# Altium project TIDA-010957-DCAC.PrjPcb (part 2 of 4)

## Sheet TIDA-010957-DCAC-Switching-Stage-GaN-TOLT.SchDoc
size 558 x 431 mm; Date: Not shown in title block; ApprovedBy: Not shown in title block; CheckedBy: Not shown in title block; Author: Not shown in title block; CompanyName: Not shown in title block; Engineer: Not shown in title block; Organization: Not shown in title block; Address1: Not shown in title block; Address2: Not shown in title block; Address3: Not shown in title block; Address4: Not shown in title block; DocumentNumber: 1; Revision: Use project parameter SCH_Rev; SheetNumber: 12; SheetTotal: 12; PageSetup: Record=PageOptions¦CenterHorizontal=True¦CenterVertical=True¦PrintScale=1.00¦XCorrection=1.00¦YCorrection=1.00¦PrintKind=0¦BorderSize=5000000¦LeftOffset=0¦BottomOffset=0¦Orientation=2¦PaperLength=1000¦PaperWidth=1000¦Scale=100¦PaperSource=15¦PrintQuality=600¦MediaType=1¦DitherType=10¦PaperKind=Letter¦PrintScaleMode=1
Used 4 times, as channels N, L1, L2, L3. Parts and nets are listed once, with the designators drawn on the sheet.

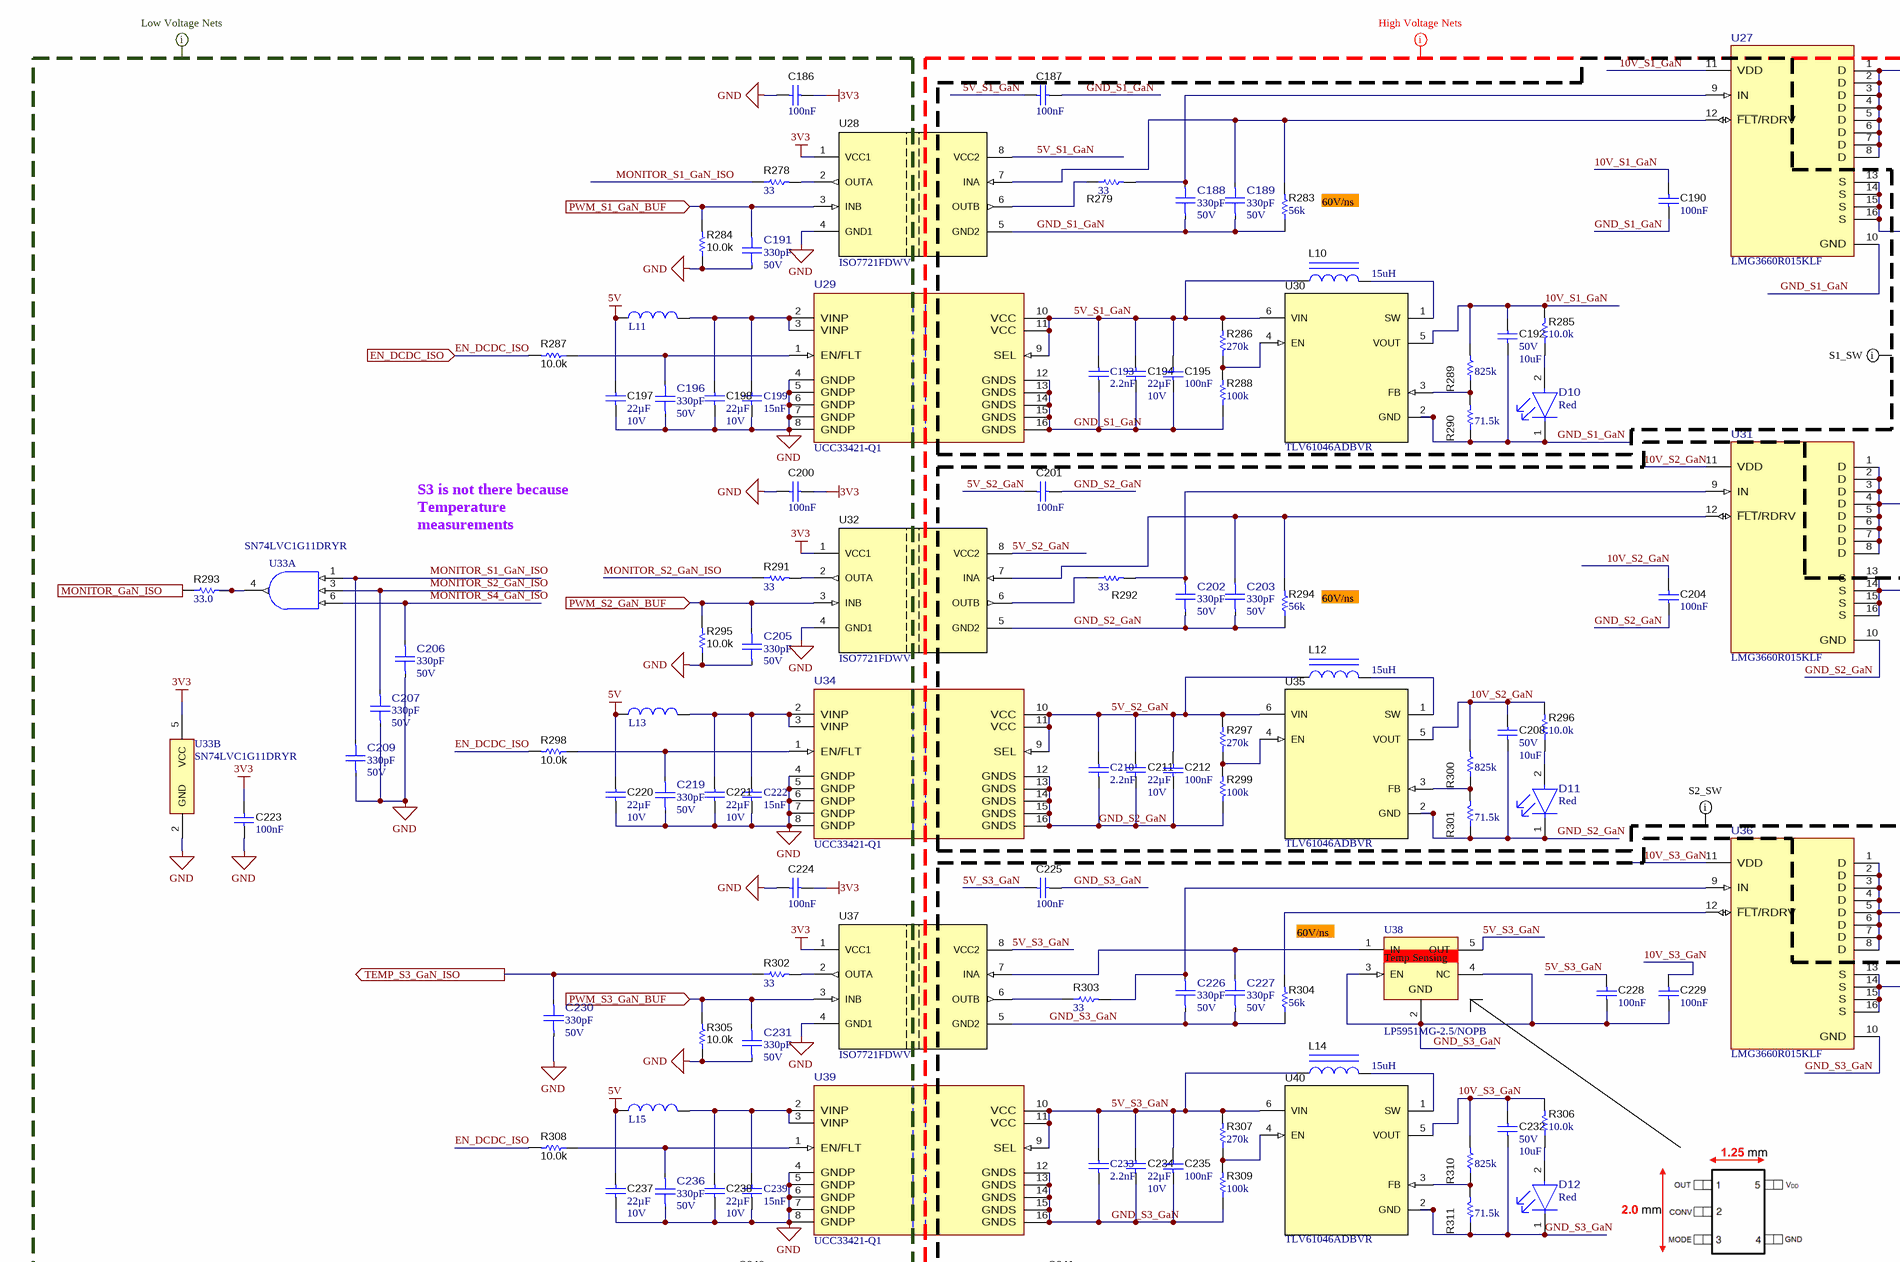
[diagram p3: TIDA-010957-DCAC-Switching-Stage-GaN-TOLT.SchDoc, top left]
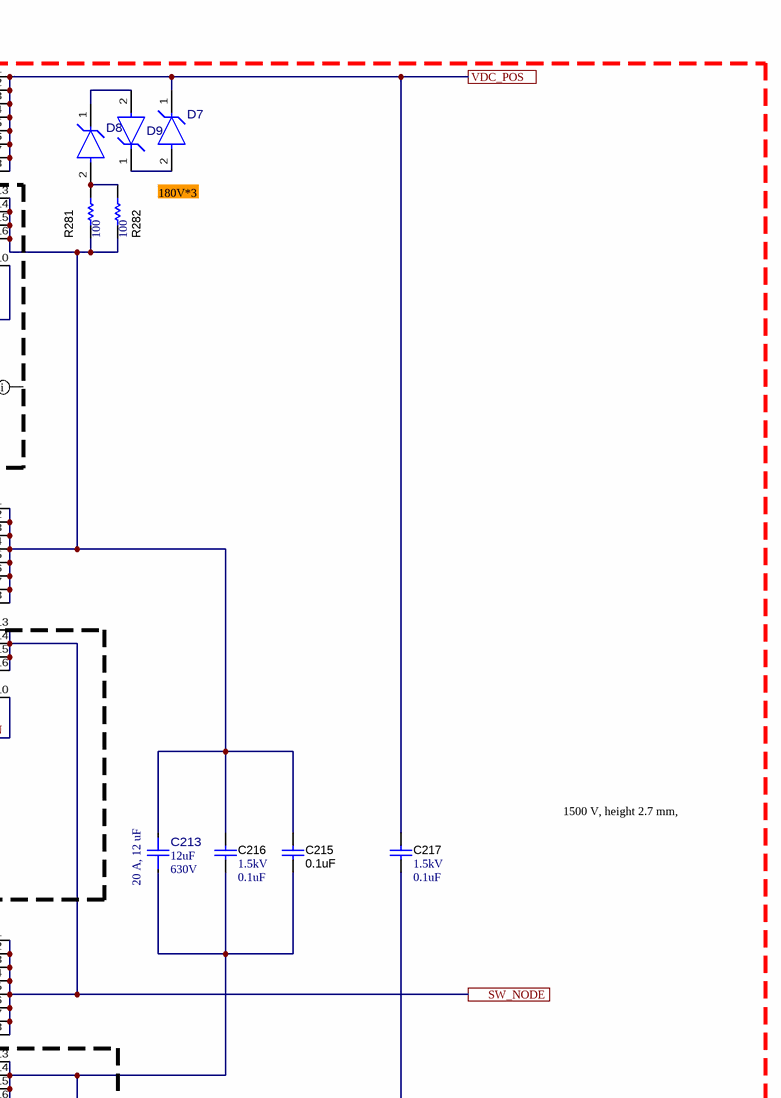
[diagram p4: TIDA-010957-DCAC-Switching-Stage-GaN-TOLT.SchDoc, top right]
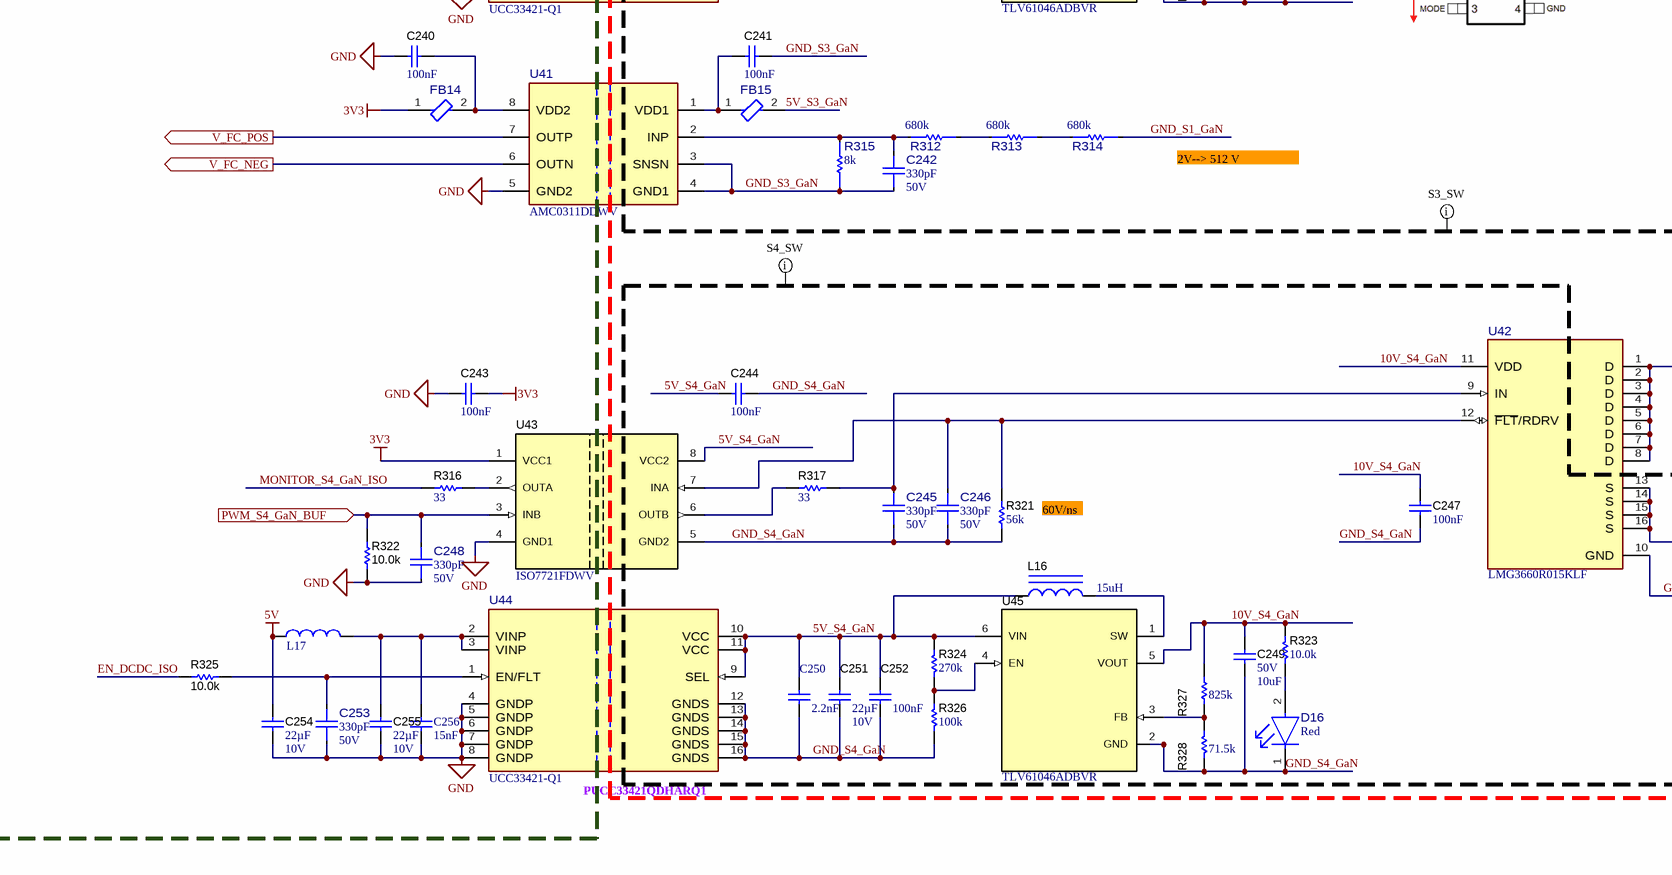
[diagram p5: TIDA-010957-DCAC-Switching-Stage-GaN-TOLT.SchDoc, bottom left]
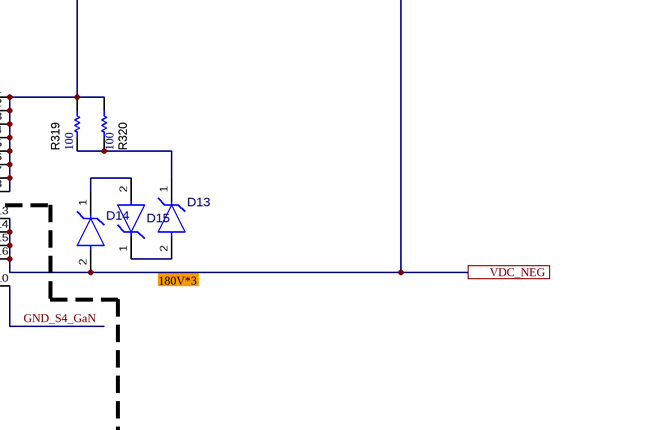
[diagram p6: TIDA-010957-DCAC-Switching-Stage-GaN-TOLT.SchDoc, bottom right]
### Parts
C186  Cap_F: 100nF  [0603]  (hidden comment: 06033C104JAT2A)
C187  Cap_F: 100nF  [0603]  (hidden comment: 06033C104JAT2A)
C188  ValueDisplayed: 330pF  VDC_V: 50V  [FP-CGA3E2C0G1H331J080AA_0603-MFG]  (hidden comment: CGA3E2C0G1H331J080AA)
C189  ValueDisplayed: 330pF  VDC_V: 50V  [FP-CGA3E2C0G1H331J080AA_0603-MFG]  (hidden comment: CGA3E2C0G1H331J080AA)
C190  Cap_F: 100nF  [0603]  (hidden comment: 06033C104JAT2A)
C191  ValueDisplayed: 330pF  VDC_V: 50V  [FP-CGA3E2C0G1H331J080AA_0603-MFG]  (hidden comment: CGA3E2C0G1H331J080AA)
C192  VDC_V: 50V  ValueDisplayed: 10uF  [1206_180]  (hidden comment: GRT31CR61H106KE01L)
C193  Cap_F: 2.2nF  [WCAP-CSGP_0402_L1W0.5H0.5]  (hidden comment: 885012205063)
C194  Cap_F: 22µF  VDC_V: 10V  [0805_HV]  (hidden comment: GRM21BZ71A226ME15L)
C195  Cap_F: 100nF  [0603]  (hidden comment: 06033C104JAT2A)
C196  ValueDisplayed: 330pF  VDC_V: 50V  [FP-CGA3E2C0G1H331J080AA_0603-MFG]  (hidden comment: CGA3E2C0G1H331J080AA)
C197  Cap_F: 22µF  VDC_V: 10V  [0805_HV]  (hidden comment: GRM21BZ71A226ME15L)
C198  Cap_F: 22µF  VDC_V: 10V  [0805_HV]  (hidden comment: GRM21BZ71A226ME15L)
C199  Cap_F: 15nF  [WCAP-CSGP_0402_L1W0.5H0.5]  (hidden comment: 885012205051)
C200  Cap_F: 100nF  [0603]  (hidden comment: 06033C104JAT2A)
C201  Cap_F: 100nF  [0603]  (hidden comment: 06033C104JAT2A)
C202  ValueDisplayed: 330pF  VDC_V: 50V  [FP-CGA3E2C0G1H331J080AA_0603-MFG]  (hidden comment: CGA3E2C0G1H331J080AA)
C203  ValueDisplayed: 330pF  VDC_V: 50V  [FP-CGA3E2C0G1H331J080AA_0603-MFG]  (hidden comment: CGA3E2C0G1H331J080AA)
C204  Cap_F: 100nF  [0603]  (hidden comment: 06033C104JAT2A)
C205  ValueDisplayed: 330pF  VDC_V: 50V  [FP-CGA3E2C0G1H331J080AA_0603-MFG]  (hidden comment: CGA3E2C0G1H331J080AA)
C206  ValueDisplayed: 330pF  VDC_V: 50V  [FP-CGA3E2C0G1H331J080AA_0603-MFG]  (hidden comment: CGA3E2C0G1H331J080AA)
C207  ValueDisplayed: 330pF  VDC_V: 50V  [FP-CGA3E2C0G1H331J080AA_0603-MFG]  (hidden comment: CGA3E2C0G1H331J080AA)
C208  VDC_V: 50V  ValueDisplayed: 10uF  [1206_180]  (hidden comment: GRT31CR61H106KE01L)
C209  ValueDisplayed: 330pF  VDC_V: 50V  [FP-CGA3E2C0G1H331J080AA_0603-MFG]  (hidden comment: CGA3E2C0G1H331J080AA)
C210  Cap_F: 2.2nF  [WCAP-CSGP_0402_L1W0.5H0.5]  (hidden comment: 885012205063)
C211  Cap_F: 22µF  VDC_V: 10V  [0805_HV]  (hidden comment: GRM21BZ71A226ME15L)
C212  Cap_F: 100nF  [0603]  (hidden comment: 06033C104JAT2A)
C213  ValueDisplayed: 12uF  VDC_V: 630V  [FP-B32676G6126K000_RADIAL-MFG]  (hidden comment: B32676G6126K000)
C215  ValueDisplayed: 0.1uF  [1812_254]  (hidden comment: C1812W104KDRACTU)
C216  VDC_V: 1.5kV  ValueDisplayed: 0.1uF  [2225]  (hidden comment: C2225C104KFRACTU)
C217  VDC_V: 1.5kV  ValueDisplayed: 0.1uF  [2225]  (hidden comment: C2225C104KFRACTU)
C219  ValueDisplayed: 330pF  VDC_V: 50V  [FP-CGA3E2C0G1H331J080AA_0603-MFG]  (hidden comment: CGA3E2C0G1H331J080AA)
C220  Cap_F: 22µF  VDC_V: 10V  [0805_HV]  (hidden comment: GRM21BZ71A226ME15L)
C221  Cap_F: 22µF  VDC_V: 10V  [0805_HV]  (hidden comment: GRM21BZ71A226ME15L)
C222  Cap_F: 15nF  [WCAP-CSGP_0402_L1W0.5H0.5]  (hidden comment: 885012205051)
C223  Cap_F: 100nF  [0603]  (hidden comment: 06033C104JAT2A)
C224  Cap_F: 100nF  [0603]  (hidden comment: 06033C104JAT2A)
C225  Cap_F: 100nF  [0603]  (hidden comment: 06033C104JAT2A)
C226  ValueDisplayed: 330pF  VDC_V: 50V  [FP-CGA3E2C0G1H331J080AA_0603-MFG]  (hidden comment: CGA3E2C0G1H331J080AA)
C227  ValueDisplayed: 330pF  VDC_V: 50V  [FP-CGA3E2C0G1H331J080AA_0603-MFG]  (hidden comment: CGA3E2C0G1H331J080AA)
C228  Cap_F: 100nF  [0603]  (hidden comment: 06033C104JAT2A)
C229  Cap_F: 100nF  [0603]  (hidden comment: 06033C104JAT2A)
C230  ValueDisplayed: 330pF  VDC_V: 50V  [FP-CGA3E2C0G1H331J080AA_0603-MFG]  (hidden comment: CGA3E2C0G1H331J080AA)
C231  ValueDisplayed: 330pF  VDC_V: 50V  [FP-CGA3E2C0G1H331J080AA_0603-MFG]  (hidden comment: CGA3E2C0G1H331J080AA)
C232  VDC_V: 50V  ValueDisplayed: 10uF  [1206_180]  (hidden comment: GRT31CR61H106KE01L)
C233  Cap_F: 2.2nF  [WCAP-CSGP_0402_L1W0.5H0.5]  (hidden comment: 885012205063)
C234  Cap_F: 22µF  VDC_V: 10V  [0805_HV]  (hidden comment: GRM21BZ71A226ME15L)
C235  Cap_F: 100nF  [0603]  (hidden comment: 06033C104JAT2A)
C236  ValueDisplayed: 330pF  VDC_V: 50V  [FP-CGA3E2C0G1H331J080AA_0603-MFG]  (hidden comment: CGA3E2C0G1H331J080AA)
C237  Cap_F: 22µF  VDC_V: 10V  [0805_HV]  (hidden comment: GRM21BZ71A226ME15L)
C238  Cap_F: 22µF  VDC_V: 10V  [0805_HV]  (hidden comment: GRM21BZ71A226ME15L)
C239  Cap_F: 15nF  [WCAP-CSGP_0402_L1W0.5H0.5]  (hidden comment: 885012205051)
C240  Cap_F: 100nF  [0603]  (hidden comment: 06033C104JAT2A)
C241  Cap_F: 100nF  [0603]  (hidden comment: 06033C104JAT2A)
C242  ValueDisplayed: 330pF  VDC_V: 50V  [FP-CGA3E2C0G1H331J080AA_0603-MFG]  (hidden comment: CGA3E2C0G1H331J080AA)
C243  Cap_F: 100nF  [0603]  (hidden comment: 06033C104JAT2A)
C244  Cap_F: 100nF  [0603]  (hidden comment: 06033C104JAT2A)
C245  ValueDisplayed: 330pF  VDC_V: 50V  [FP-CGA3E2C0G1H331J080AA_0603-MFG]  (hidden comment: CGA3E2C0G1H331J080AA)
C246  ValueDisplayed: 330pF  VDC_V: 50V  [FP-CGA3E2C0G1H331J080AA_0603-MFG]  (hidden comment: CGA3E2C0G1H331J080AA)
C247  Cap_F: 100nF  [0603]  (hidden comment: 06033C104JAT2A)
C248  ValueDisplayed: 330pF  VDC_V: 50V  [FP-CGA3E2C0G1H331J080AA_0603-MFG]  (hidden comment: CGA3E2C0G1H331J080AA)
C249  VDC_V: 50V  ValueDisplayed: 10uF  [1206_180]  (hidden comment: GRT31CR61H106KE01L)
C250  Cap_F: 2.2nF  [WCAP-CSGP_0402_L1W0.5H0.5]  (hidden comment: 885012205063)
C251  Cap_F: 22µF  VDC_V: 10V  [0805_HV]  (hidden comment: GRM21BZ71A226ME15L)
C252  Cap_F: 100nF  [0603]  (hidden comment: 06033C104JAT2A)
C253  ValueDisplayed: 330pF  VDC_V: 50V  [FP-CGA3E2C0G1H331J080AA_0603-MFG]  (hidden comment: CGA3E2C0G1H331J080AA)
C254  Cap_F: 22µF  VDC_V: 10V  [0805_HV]  (hidden comment: GRM21BZ71A226ME15L)
C255  Cap_F: 22µF  VDC_V: 10V  [0805_HV]  (hidden comment: GRM21BZ71A226ME15L)
C256  Cap_F: 15nF  [WCAP-CSGP_0402_L1W0.5H0.5]  (hidden comment: 885012205051)
D7  ZGL41-180A-E3/96  [FP-ZGL41-180A-E3/96_GL41-MFG]  (value not drawn)
D8  ZGL41-180A-E3/96  [FP-ZGL41-180A-E3/96_GL41-MFG]  (value not drawn)
D9  ZGL41-180A-E3/96  [FP-ZGL41-180A-E3/96_GL41-MFG]  (value not drawn)
D10  Color: Red  [FP-APG1608SURKC_T_0603-MFG]  (hidden comment: APG1608SURKC/T)
D11  Color: Red  [FP-APG1608SURKC_T_0603-MFG]  (hidden comment: APG1608SURKC/T)
D12  Color: Red  [FP-APG1608SURKC_T_0603-MFG]  (hidden comment: APG1608SURKC/T)
D13  ZGL41-180A-E3/96  [FP-ZGL41-180A-E3/96_GL41-MFG]  (value not drawn)
D14  ZGL41-180A-E3/96  [FP-ZGL41-180A-E3/96_GL41-MFG]  (value not drawn)
D15  ZGL41-180A-E3/96  [FP-ZGL41-180A-E3/96_GL41-MFG]  (value not drawn)
D16  Color: Red  [FP-APG1608SURKC_T_0603-MFG]  (hidden comment: APG1608SURKC/T)
FB14  MH1608-601Y  [FP-MH1608-601Y_0603-MFG]  (value not drawn)
FB15  MH1608-601Y  [FP-MH1608-601Y_0603-MFG]  (value not drawn)
L10  ValueDisplayed: 15uH  [SDR0302]  (hidden comment: SDR0302-150ML)
L11  74479763222  [WE-PMI_0603_L1.6W0.8H0.8]  (value not drawn)
L12  ValueDisplayed: 15uH  [SDR0302]  (hidden comment: SDR0302-150ML)
L13  74479763222  [WE-PMI_0603_L1.6W0.8H0.8]  (value not drawn)
L14  ValueDisplayed: 15uH  [SDR0302]  (hidden comment: SDR0302-150ML)
L15  74479763222  [WE-PMI_0603_L1.6W0.8H0.8]  (value not drawn)
L16  ValueDisplayed: 15uH  [SDR0302]  (hidden comment: SDR0302-150ML)
L17  74479763222  [WE-PMI_0603_L1.6W0.8H0.8]  (value not drawn)
R278  ValueDisplayed: 33  [0603]  (hidden comment: CRCW060333R0JNEA)
R279  ValueDisplayed: 33  [0603]  (hidden comment: CRCW060333R0JNEA)
R281  ValueDisplayed: 100  [1206]  (hidden comment: CRCW1206100RFKEAHP)
R282  ValueDisplayed: 100  [1206]  (hidden comment: CRCW1206100RFKEAHP)
R283  ValueDisplayed: 56k  [0603]  (hidden comment: CRCW060356K0JNEA)
R284  ValueDisplayed: 10.0k  [0603]  (hidden comment: CRCW060310K0FKEA)
R285  ValueDisplayed: 10.0k  [0603]  (hidden comment: RC0603FR-0710KL)
R286  ValueDisplayed: 270k  [0603]  (hidden comment: RC0603FR-07270KL)
R287  ValueDisplayed: 10.0k  [0603]  (hidden comment: CRCW060310K0FKEA)
R288  ValueDisplayed: 100k  [0603]  (hidden comment: RC0603FR-07100KL)
R289  ValueDisplayed: 825k  [0603]  (hidden comment: RC0603FR-07825KL)
R290  ValueDisplayed: 71.5k  [0603]  (hidden comment: RC0603FR-0771K5L)
R291  ValueDisplayed: 33  [0603]  (hidden comment: CRCW060333R0JNEA)
R292  ValueDisplayed: 33  [0603]  (hidden comment: CRCW060333R0JNEA)
R293  ValueDisplayed: 33.0  [0402L]  (hidden comment: ERJ-2RKF33R0X)
R294  ValueDisplayed: 56k  [0603]  (hidden comment: CRCW060356K0JNEA)
R295  ValueDisplayed: 10.0k  [0603]  (hidden comment: CRCW060310K0FKEA)
R296  ValueDisplayed: 10.0k  [0603]  (hidden comment: RC0603FR-0710KL)
R297  ValueDisplayed: 270k  [0603]  (hidden comment: RC0603FR-07270KL)
R298  ValueDisplayed: 10.0k  [0603]  (hidden comment: CRCW060310K0FKEA)
R299  ValueDisplayed: 100k  [0603]  (hidden comment: RC0603FR-07100KL)
R300  ValueDisplayed: 825k  [0603]  (hidden comment: RC0603FR-07825KL)
R301  ValueDisplayed: 71.5k  [0603]  (hidden comment: RC0603FR-0771K5L)
R302  ValueDisplayed: 33  [0603]  (hidden comment: CRCW060333R0JNEA)
R303  ValueDisplayed: 33  [0603]  (hidden comment: CRCW060333R0JNEA)
R304  ValueDisplayed: 56k  [0603]  (hidden comment: CRCW060356K0JNEA)
R305  ValueDisplayed: 10.0k  [0603]  (hidden comment: CRCW060310K0FKEA)
R306  ValueDisplayed: 10.0k  [0603]  (hidden comment: RC0603FR-0710KL)
R307  ValueDisplayed: 270k  [0603]  (hidden comment: RC0603FR-07270KL)
R308  ValueDisplayed: 10.0k  [0603]  (hidden comment: CRCW060310K0FKEA)
R309  ValueDisplayed: 100k  [0603]  (hidden comment: RC0603FR-07100KL)
R310  ValueDisplayed: 825k  [0603]  (hidden comment: RC0603FR-07825KL)
R311  ValueDisplayed: 71.5k  [0603]  (hidden comment: RC0603FR-0771K5L)
R312  value 680k  [FP-TNPV0805680KBEEA_0805-MFG]  (hidden comment: TNPV0805680KBEEA)
R313  value 680k  [FP-TNPV0805680KBEEA_0805-MFG]  (hidden comment: TNPV0805680KBEEA)
R314  value 680k  [FP-TNPV0805680KBEEA_0805-MFG]  (hidden comment: TNPV0805680KBEEA)
R315  value 8k  [FP-RT0603BRE078KL_0603-MFG]  (hidden comment: RT0603BRE078KL)
R316  ValueDisplayed: 33  [0603]  (hidden comment: CRCW060333R0JNEA)
R317  ValueDisplayed: 33  [0603]  (hidden comment: CRCW060333R0JNEA)
R319  ValueDisplayed: 100  [1206]  (hidden comment: CRCW1206100RFKEAHP)
R320  ValueDisplayed: 100  [1206]  (hidden comment: CRCW1206100RFKEAHP)
R321  ValueDisplayed: 56k  [0603]  (hidden comment: CRCW060356K0JNEA)
R322  ValueDisplayed: 10.0k  [0603]  (hidden comment: CRCW060310K0FKEA)
R323  ValueDisplayed: 10.0k  [0603]  (hidden comment: RC0603FR-0710KL)
R324  ValueDisplayed: 270k  [0603]  (hidden comment: RC0603FR-07270KL)
R325  ValueDisplayed: 10.0k  [0603]  (hidden comment: CRCW060310K0FKEA)
R326  ValueDisplayed: 100k  [0603]  (hidden comment: RC0603FR-07100KL)
R327  ValueDisplayed: 825k  [0603]  (hidden comment: RC0603FR-07825KL)
R328  ValueDisplayed: 71.5k  [0603]  (hidden comment: RC0603FR-0771K5L)
U27  LMG3660R015KLF  [KLF0016A-MFG]
U28  ISO7721FDWV  [DWV0008A]
U29  UCC33421-Q1  [DWX0016A-MFG]
U30  TLV61046ADBVR  [DBV0006A_N]
U31  LMG3660R015KLF  [KLF0016A-MFG]
U32  ISO7721FDWV  [DWV0008A]
U33  SN74LVC1G11DRYR  [DRY0006A]  (parts A,B of 2)
U34  UCC33421-Q1  [DWX0016A-MFG]
U35  TLV61046ADBVR  [DBV0006A_N]
U36  LMG3660R015KLF  [KLF0016A-MFG]
U37  ISO7721FDWV  [DWV0008A]
U38  LP5951MG-2.5/NOPB  [DCK0005A_N]
U39  UCC33421-Q1  [DWX0016A-MFG]
U40  TLV61046ADBVR  [DBV0006A_N]
U41  AMC0311DDWV  [DWV0008A-MFG]
U42  LMG3660R015KLF  [KLF0016A-MFG]
U43  ISO7721FDWV  [DWV0008A]
U44  UCC33421-Q1  [DWX0016A-MFG]
U45  TLV61046ADBVR  [DBV0006A_N]

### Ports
EN_DCDC_ISO (in), MONITOR_GaN_ISO (out), PWM_S1_GaN_BUF (in), PWM_S2_GaN_BUF (in), PWM_S3_GaN_BUF (in), PWM_S4_GaN_BUF (in), SW_NODE, TEMP_S3_GaN_ISO (out), V_FC_NEG (out), V_FC_POS (out), VDC_NEG, VDC_POS

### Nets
3V3: C186.1 C200.1 C223.1 C224.1 C243.1 FB14.1 U28.1(VCC1) U32.1(VCC1) U33.5(VCC) U37.1(VCC1) U43.1(VCC1)
5V: C197.1 C220.1 C237.1 C254.1 L11.2 L13.2 L15.2 L17.2
GND: C186.2 C191.1 C196.1 C197.2 C198.2 C199.1 C200.2 C205.1 C206.1 C207.1 C209.1 C219.1 C220.2 C221.2 C222.1 C223.2 C224.2 C230.1 C231.1 C236.1 C237.2 C238.2 C239.1 C240.2 C243.2 C248.1 C253.1 C254.2 C255.2 C256.1 R284.1 R295.1 R305.1 R322.1 U28.4(GND1) U29.4(GNDP) U29.5(GNDP) U29.6(GNDP) U29.7(GNDP) U29.8(GNDP) U32.4(GND1) U33.2(GND) U34.4(GNDP) U34.5(GNDP) U34.6(GNDP) U34.7(GNDP) U34.8(GNDP) U37.4(GND1) U39.4(GNDP) U39.5(GNDP) U39.6(GNDP) U39.7(GNDP) U39.8(GNDP) U41.5(GND2) U43.4(GND1) U44.4(GNDP) U44.5(GNDP) U44.6(GNDP) U44.7(GNDP) U44.8(GNDP)
5V_S1_GaN: C187.1 C193.2 C194.1 C195.1 L10.2 R286.2 U28.8(VCC2) U29.9(SEL) U29.10(VCC) U29.11(VCC) U30.6(VIN)
5V_S2_GaN: C201.1 C210.2 C211.1 C212.1 L12.2 R297.2 U32.8(VCC2) U34.9(SEL) U34.10(VCC) U34.11(VCC) U35.6(VIN)
5V_S3_GaN: C225.1 C228.1 C233.2 C234.1 C235.1 FB15.2 L14.2 R307.2 U37.8(VCC2) U38.5(OUT) U39.9(SEL) U39.10(VCC) U39.11(VCC) U40.6(VIN)
5V_S4_GaN: C244.1 C250.2 C251.1 C252.1 L16.2 R324.2 U43.8(VCC2) U44.9(SEL) U44.10(VCC) U44.11(VCC) U45.6(VIN)
10V_S1_GaN: C190.1 C192.1 R285.2 R289.2 U27.11(VDD) U30.5(VOUT)
10V_S2_GaN: C204.1 C208.1 R296.2 R300.2 U31.11(VDD) U35.5(VOUT)
10V_S3_GaN: C229.1 C232.1 R306.2 R310.2 U36.11(VDD) U40.5(VOUT)
10V_S4_GaN: C247.1 C249.1 R323.2 R327.2 U42.11(VDD) U45.5(VOUT)
EN_DCDC_ISO: R287.2 R298.2 R308.2 R325.2 ; port EN_DCDC_ISO
GND_S1_GaN: C187.2 C188.1 C189.1 C190.2 C192.2 C193.1 C194.2 C195.2 D10.1(CATHODE) R283.1 R288.1 R290.1 R314.2 U27.10(GND) U28.5(GND2) U29.12(GNDS) U29.13(GNDS) U29.14(GNDS) U29.15(GNDS) U29.16(GNDS) U30.2(GND)
GND_S2_GaN: C201.2 C202.1 C203.1 C204.2 C208.2 C210.1 C211.2 C212.2 D11.1(CATHODE) R294.1 R299.1 R301.1 U31.10(GND) U32.5(GND2) U34.12(GNDS) U34.13(GNDS) U34.14(GNDS) U34.15(GNDS) U34.16(GNDS) U35.2(GND)
GND_S3_GaN: C225.2 C226.1 C227.1 C228.2 C229.2 C232.2 C233.1 C234.2 C235.2 C241.2 C242.1 D12.1(CATHODE) R304.1 R309.1 R311.1 R315.1 U36.10(GND) U37.5(GND2) U38.2(GND) U38.3(EN) U38.4(NC) U39.12(GNDS) U39.13(GNDS) U39.14(GNDS) U39.15(GNDS) U39.16(GNDS) U40.2(GND) U41.3(SNSN) U41.4(GND1)
GND_S4_GaN: C244.2 C245.1 C246.1 C247.2 C249.2 C250.1 C251.2 C252.2 D16.1(CATHODE) R321.1 R326.1 R328.1 U42.10(GND) U43.5(GND2) U44.12(GNDS) U44.13(GNDS) U44.14(GNDS) U44.15(GNDS) U44.16(GNDS) U45.2(GND)
MONITOR_GaN_ISO: R293.1 ; port MONITOR_GaN_ISO
MONITOR_S1_GaN_ISO: C209.2 R278.1 U33.1(A)
MONITOR_S2_GaN_ISO: C207.2 R291.1 U33.3(B)
MONITOR_S4_GaN_ISO: C206.2 R316.1 U33.6(C)
PWM_S1_GaN_BUF: C191.2 R284.2 U28.3(INB) ; port PWM_S1_GaN_BUF
PWM_S2_GaN_BUF: C205.2 R295.2 U32.3(INB) ; port PWM_S2_GaN_BUF
PWM_S3_GaN_BUF: C231.2 R305.2 U37.3(INB) ; port PWM_S3_GaN_BUF
PWM_S4_GaN_BUF: C248.2 R322.2 U43.3(INB) ; port PWM_S4_GaN_BUF
SW_NODE: U31.13(S) U31.14(S) U31.15(S) U31.16(S) U36.1(D) U36.2(D) U36.3(D) U36.4(D) U36.5(D) U36.6(D) U36.7(D) U36.8(D) ; port SW_NODE
TEMP_S3_GaN_ISO: C230.2 R302.1 ; port TEMP_S3_GaN_ISO
V_FC_NEG: U41.6(OUTN) ; port V_FC_NEG
V_FC_POS: U41.7(OUTP) ; port V_FC_POS
VDC_NEG: C217.2 D14.2(ANODE) U42.13(S) U42.14(S) U42.15(S) U42.16(S) ; port VDC_NEG
VDC_POS: C217.1 D7.1(CATHODE) U27.1(D) U27.2(D) U27.3(D) U27.4(D) U27.5(D) U27.6(D) U27.7(D) U27.8(D) ; port VDC_POS
NetC188_2: C188.2 R279.2 U27.9(IN)
NetC189_2: C189.2 R283.2 U27.12(~{FLT}/RDRV) U28.7(INA)
NetC196_2: C196.2 R287.1 U29.1(EN/FLT)
NetC198_1: C198.1 C199.2 L11.1 U29.2(VINP) U29.3(VINP)
NetC202_2: C202.2 R292.2 U31.9(IN)
NetC203_2: C203.2 R294.2 U31.12(~{FLT}/RDRV) U32.7(INA)
NetC213_1: C213.1 C215.1 C216.2 R319.2 R320.2 U36.13(S) U36.14(S) U36.15(S) U36.16(S) U42.1(D) U42.2(D) U42.3(D) U42.4(D) U42.5(D) U42.6(D) U42.7(D) U42.8(D)
NetC213_2: C213.2 C215.2 C216.1 R281.1 R282.1 U27.13(S) U27.14(S) U27.15(S) U27.16(S) U31.1(D) U31.2(D) U31.3(D) U31.4(D) U31.5(D) U31.6(D) U31.7(D) U31.8(D)
NetC219_2: C219.2 R298.1 U34.1(EN/FLT)
NetC221_1: C221.1 C222.2 L13.1 U34.2(VINP) U34.3(VINP)
NetC226_2: C226.2 R303.2 U36.9(IN)
NetC227_2: C227.2 U37.7(INA) U38.1(IN)
NetC236_2: C236.2 R308.1 U39.1(EN/FLT)
NetC238_1: C238.1 C239.2 L15.1 U39.2(VINP) U39.3(VINP)
NetC240_1: C240.1 FB14.2 U41.8(VDD2)
NetC241_1: C241.1 FB15.1 U41.1(VDD1)
NetC242_2: C242.2 R312.1 R315.2 U41.2(INP)
NetC245_2: C245.2 R317.2 U42.9(IN)
NetC246_2: C246.2 R321.2 U42.12(~{FLT}/RDRV) U43.7(INA)
NetC253_2: C253.2 R325.1 U44.1(EN/FLT)
NetC255_1: C255.1 C256.2 L17.1 U44.2(VINP) U44.3(VINP)
NetD7_2: D7.2(ANODE) D9.1(CATHODE)
NetD8_1: D8.1(CATHODE) D9.2(ANODE)
NetD8_2: D8.2(ANODE) R281.2 R282.2
NetD10_2: D10.2(ANODE) R285.1
NetD11_2: D11.2(ANODE) R296.1
NetD12_2: D12.2(ANODE) R306.1
NetD13_1: D13.1(CATHODE) R319.1 R320.1
NetD13_2: D13.2(ANODE) D15.1(CATHODE)
NetD14_1: D14.1(CATHODE) D15.2(ANODE)
NetD16_2: D16.2(ANODE) R323.1
NetL10_1: L10.1 U30.1(SW)
NetL12_1: L12.1 U35.1(SW)
NetL14_1: L14.1 U40.1(SW)
NetL16_1: L16.1 U45.1(SW)
NetR278_2: R278.2 U28.2(OUTA)
NetR279_1: R279.1 U28.6(OUTB)
NetR286_1: R286.1 R288.2 U30.4(EN)
NetR289_1: R289.1 R290.2 U30.3(FB)
NetR291_2: R291.2 U32.2(OUTA)
NetR292_1: R292.1 U32.6(OUTB)
NetR293_2: R293.2 U33.4(Y)
NetR297_1: R297.1 R299.2 U35.4(EN)
NetR300_1: R300.1 R301.2 U35.3(FB)
NetR302_2: R302.2 U37.2(OUTA)
NetR303_1: R303.1 U37.6(OUTB)
NetR304_2: R304.2 U36.12(~{FLT}/RDRV)
NetR307_1: R307.1 R309.2 U40.4(EN)
NetR310_1: R310.1 R311.2 U40.3(FB)
NetR312_2: R312.2 R313.1
NetR313_2: R313.2 R314.1
NetR316_2: R316.2 U43.2(OUTA)
NetR317_1: R317.1 U43.6(OUTB)
NetR324_1: R324.1 R326.2 U45.4(EN)
NetR327_1: R327.1 R328.2 U45.3(FB)

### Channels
N: designators end in _N; ports EN_DCDC_ISO=EN_AUX_ISO_DCAC MONITOR_GaN_ISO=MONITOR_GaN_ISO_N PWM_S1_GaN_BUF=PWM_S1_GaN_BUF_N PWM_S2_GaN_BUF=PWM_S2_GaN_BUF_N PWM_S3_GaN_BUF=PWM_S3_GaN_BUF_N PWM_S4_GaN_BUF=PWM_S4_GaN_BUF_N SW_NODE=SN_LN TEMP_S3_GaN_ISO=TEMP_S3_GaN_ISO_N V_FC_NEG=V_FC_NEG_N V_FC_POS=V_FC_POS_N VDC_NEG=VDC-_REF VDC_POS=VDC+
L1: designators end in _L1; ports EN_DCDC_ISO=EN_AUX_ISO_DCAC MONITOR_GaN_ISO=MONITOR_GaN_ISO_L1 PWM_S1_GaN_BUF=PWM_S1_GaN_BUF_L1 PWM_S2_GaN_BUF=PWM_S2_GaN_BUF_L1 PWM_S3_GaN_BUF=PWM_S3_GaN_BUF_L1 PWM_S4_GaN_BUF=PWM_S4_GaN_BUF_L1 SW_NODE=SN_L1 TEMP_S3_GaN_ISO=TEMP_S3_GaN_ISO_L1 V_FC_NEG=V_FC_NEG_L1 V_FC_POS=V_FC_POS_L1 VDC_NEG=VDC-_REF VDC_POS=VDC+
L2: designators end in _L2; ports EN_DCDC_ISO=EN_AUX_ISO_DCAC MONITOR_GaN_ISO=MONITOR_GaN_ISO_L2 PWM_S1_GaN_BUF=PWM_S1_GaN_BUF_L2 PWM_S2_GaN_BUF=PWM_S2_GaN_BUF_L2 PWM_S3_GaN_BUF=PWM_S3_GaN_BUF_L2 PWM_S4_GaN_BUF=PWM_S4_GaN_BUF_L2 SW_NODE=SN_L2 TEMP_S3_GaN_ISO=TEMP_S3_GaN_ISO_L2 V_FC_NEG=V_FC_NEG_L2 V_FC_POS=V_FC_POS_L2 VDC_NEG=VDC-_REF VDC_POS=VDC+
L3: designators end in _L3; ports EN_DCDC_ISO=EN_AUX_ISO_DCAC MONITOR_GaN_ISO=MONITOR_GaN_ISO_L3 PWM_S1_GaN_BUF=PWM_S1_GaN_BUF_L3 PWM_S2_GaN_BUF=PWM_S2_GaN_BUF_L3 PWM_S3_GaN_BUF=PWM_S3_GaN_BUF_L3 PWM_S4_GaN_BUF=PWM_S4_GaN_BUF_L3 SW_NODE=SN_L3 TEMP_S3_GaN_ISO=TEMP_S3_GaN_ISO_L3 V_FC_NEG=V_FC_NEG_L3 V_FC_POS=V_FC_POS_L3 VDC_NEG=VDC-_REF VDC_POS=VDC+

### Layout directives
net class LV_NET: 3V3, 5V, EN_DCDC_ISO, GND, MONITOR_S1_GaN_ISO, MONITOR_S2_GaN_ISO, MONITOR_S4_GaN_ISO
net class HV_NET: 5V_S1_GaN, 5V_S2_GaN, 5V_S3_GaN, 5V_S4_GaN, 10V_S1_GaN, 10V_S2_GaN, 10V_S3_GaN, 10V_S4_GaN, GND_S1_GaN, GND_S2_GaN, GND_S3_GaN, GND_S4_GaN
net class S4_SW: 5V_S1_GaN, 5V_S2_GaN, 5V_S3_GaN, 5V_S4_GaN, 10V_S1_GaN, 10V_S2_GaN, 10V_S3_GaN, 10V_S4_GaN, GND_S1_GaN, GND_S2_GaN, GND_S3_GaN, GND_S4_GaN
net class S3_SW: 5V_S1_GaN, 5V_S2_GaN, 5V_S3_GaN, 5V_S4_GaN, 10V_S1_GaN, 10V_S2_GaN, 10V_S3_GaN, 10V_S4_GaN, GND_S1_GaN, GND_S2_GaN, GND_S3_GaN, GND_S4_GaN
net class S2_SW: 5V_S1_GaN, 5V_S2_GaN, 5V_S3_GaN, 5V_S4_GaN, 10V_S1_GaN, 10V_S2_GaN, 10V_S3_GaN, 10V_S4_GaN, GND_S1_GaN, GND_S2_GaN, GND_S3_GaN, GND_S4_GaN
net class S1_SW: 5V_S1_GaN, 5V_S2_GaN, 5V_S3_GaN, 5V_S4_GaN, 10V_S1_GaN, 10V_S2_GaN, 10V_S3_GaN, 10V_S4_GaN, GND_S1_GaN, GND_S2_GaN, GND_S3_GaN, GND_S4_GaN

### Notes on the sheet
- 180V*3
- (near R283) 60V/ns
- S3 is not there because Temperature measurements
- (near R294) 60V/ns
- 1500 V, height 2.7 mm, 100 nF,
- (near C213) 20 A, 12 uF
- 60V/ns
- (near U38) Temp Sensing
- 2V--> 512 V
- (near R321) 60V/ns
- (near U44) PUCC33421QDHARQ1

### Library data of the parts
C186 C187 C190 C195 C200 C201 C204 C212 C223-C225 C228 C229 C235 C240 C241 C243 C244 C247 C252 = CMP-0006752-5: CAP, CERM, 0.1 uF, 25 V, +/- 5%, X7R, 0603; Manufacturer: AVX; TaMin_C: -55°C; ESR_ohm: 0.05; Polarized: N; SizeAreaWB_mm2: 4.68; Value1: 0.05 ohm; U/M: EA; Value: 0.1uF; TaMax_C: 125°C; SizeZ_mm: 1; SizeX_mm: 1.6; SizeY_mm: 0.8; Value2: 25V; SizeArea_mm2: 1.28; AEC Category: Q200
C188 C189 C191 C196 C202 C203 C205-C207 C209 C219 C226 C227 C230 C231 C236 C242 C245 C246 C248 C253 = CMP-0095085-1: Cap Ceramic 330pF 50V C0G 5% Pad SMD 0603 +125°C Automotive T/R; Manufacturer: TDK; AEC Qualified: Yes; TempCo: 30ppm/°C; Tolerance_%: 0.05%; AEC Grade: Grade 1; SizeZ_mm: 1.1mm
C192 C208 C232 C249 = CMP-0009015-2: CAP, CERM, 10 uF, 50 V, +/- 10%, X5R, AEC-Q200 Grade 1, 1206; Manufacturer: MuRata; TaMin_C: -55°C; Polarized: N; SizeAreaWB_mm2: 10.92; Value1: Unknown; U/M: EA; Value: 10uF; TaMax_C: 85°C; SizeZ_mm: 1.8; SizeX_mm: 3.2; SizeY_mm: 1.6; Cap_Case: 1206; SizeArea_mm2: 5.12; AEC Qualified: Y; Cap_F: 10µF; AEC Grade: 1; AEC Category: Q200
C193 C210 C233 C250 = CMP-0119293-1: WCAP-CSGP Multilayer Ceramic Chip Capacitor, General Purpose, size 0402, X7R, 2.2nF, 50VDC; Manufacturer: Wurth Elektronik; Capacitance Tolerance: +/-10%; Case/Size Code: 0402; Dissipation Factor: 2.5%; Insulation Resistance: 10GOhm; Rated Voltage (DC): 50V; Technical Reference: X7R0402222K050DFCT10000
C194 C197 C198 C211 C220 C221 C234 C237 C238 C251 C254 C255 = CMP-0008377-2: CAP, CERM, 22 uF, 10 V, +/- 20%, X7R, 0805; Manufacturer: MuRata; SizeY_mm: 1.25; Cap_Case: 0805; SizeArea_mm2: 2.5; AEC Qualified: N; AEC Category: Q200; ValueDisplayed: 22uF; TaMin_C: -55°C; SizeAreaWB_mm2: 6.75; Value1: Unknown; U/M: EA; Value: 22uF; TaMax_C: 125°C; SizeZ_mm: 1.45; SizeX_mm: 2
C199 C222 C239 C256 = CMP-0115362-1: WCAP-CSGP Multilayer Ceramic Chip Capacitor, General Purpose, size 0402, X7R, 15nF, 25VDC; Manufacturer: Wurth Elektronik; Capacitance Tolerance: +/-10%; Case/Size Code: 0402; Dissipation Factor: 3.5%; Insulation Resistance: 10GOhm; Rated Voltage (DC): 25V; Technical Reference: X7R0402153K025DFCT10000
C213 = CMP-0124359-1: Cap Film 12uF 630V PP 10% (42 X 28 X 42.5mm) Radial 0.0055 Ohm 100°C Bulk; Manufacturer: TDK; AEC Grade: Grade 2; AEC Qualified: Yes; Cap_F: 12µF; Value: 12µF
C215 = CMP-0009326-2: CAP, CERM, 0.1 uF, 1000 V, +/- 10%, X7R, 1812; Manufacturer: Kemet; Polarized: N; Value: 0.1uF; U/M: EA; Cap_F: 100nF; Value1: Unknown; VDC_V: 1kV; Value2: 1000V; TaMin_C: -55°C; TaMax_C: 125°C; Cap_Case: 1812; AEC Category: Q200; SizeArea_mm2: 14.4; SizeAreaWB_mm2: 23.1; SizeX_mm: 4.5; SizeY_mm: 3.2; SizeZ_mm: 2.54
C216 C217 = CMP-0009331-2: CAP, CERM, 0.1 uF, 1500 V, +/- 10%, X7R, 2225; Manufacturer: Kemet; TaMin_C: -55°C; Polarized: N; SizeAreaWB_mm2: 63.91; Value1: Unknown; U/M: EA; Value: 0.1uF; TaMax_C: 125°C; SizeZ_mm: 2; SizeX_mm: 5.7; SizeY_mm: 6.3; Value2: 1500V; SizeArea_mm2: 35.91; Cap_F: 100nF; AEC Category: Q200
D7-D9 D13-D15 = CMP-0122312-1: Zener Diode 180 V 1 W ±5% Surface Mount DO-213AB (GL41); Manufacturer: Vishay; AEC Qualified: No; SizeZ_mm: 2.67mm; TJmax_C: 150°C; Vf_V: 189V; Vr_V: 136.9V; Max Reverse Leakage Current: 1uA; Power_W: 1000mW; Vz_V: 180V; Zener Impedance: 900Ω
D10-D12 D16 = CMP-0091305-2: Red 630nm LED Indication - Discrete 2V 0603 (1608 Metric); Manufacturer: Kingbright; AEC Qualified: No; Import Ts: 1521847491; Forward Current: 20mA; Vr_V: 5V; Ciiva Ids: 1546259; Luminous Intensity: 110mcd; Power_TotalModule: 75mW; Tjmax_C: 115°C; Led Orientation: Top View; SizeZ_mm: 0.28mm; LambdaP: 645nm; Angle: 120°
FB14 FB15 = CMP-0037505-1: 600 Ohms @ 100 MHz 1 Power, Signal Line Ferrite Bead 0603 (1608 Metric) 1A 200mOhm; Manufacturer: Bourns; DCR_ohm: 0.2; SizeZ_mm: 1mm; AEC Qualified: No; Impedance At Frequency: 600Ω @ 100MHz; Test Frequency: 100MHz; Tolerance_%: 25%
L10 L12 L14 L16 = CMP-0057419-2: Inductor, Drum Core, Ferrite, 15 uH, 0.65 A, 0.4 ohm, SMD; Manufacturer: Bourns; Isat: 0.86A @ 10% inductance drop; Irms: 0.65A @ 40C rise; Green_Lifecycle: Active; SizeAreaWB_mm2: 15.2; DCR_ohm: 4d; Green_REACh: Passed; Value1: 0.4 ohm; Value: 15uH; Imax_A: 6.5dA; SizeZ_mm: 2.5; SizeX_mm: 3; SizeY_mm: 2.8; Value2: 0.65A; SizeArea_mm2: 8.4; Ind_H: 15µH; AEC Category: Q200
L11 L13 L15 L17 = CMP-0100992-1: WE-PMI SMT Power Multilayer Inductor, size 0603, 2.2uH, 0.8A, 375mOhm; Manufacturer: Wurth Elektronik; Case/Size Code: 0603; Inductance Tolerance: 20%; Q Factor: 15; Saturation Current: 0.28A; Self Resonant Frequency: 80MHz; Type: Low RDC
R278 R279 R291 R292 R302 R303 R316 R317 = CMP-0025787-4: RES, 33, 5%, 0.1 W, AEC-Q200 Grade 0, 0603; Manufacturer: Vishay-Dale; Power_W: 100mW; TempCo: 200 ppm/C; Value_Code: 33R0; Value: 33; EIA_Code: E24; SizeX_mm: 1.6; SizeY_mm: 0.8; SizeZ_mm: 1; Value2: 0.1W; SizeArea_mm2: 1.28; AEC Qualified: Y; VDC_V: 75V; AEC Category: Q200; AEC Grade: 0
R281 R282 R319 R320 = CMP-0016570-3: RES, 100, 1%, 0.5 W, AEC-Q200 Grade 0, 1206; Manufacturer: Vishay-Dale; Power_W: 500mW; TempCo: 100 ppm/C; Value_Code: 100R; Value: 100; EIA_Code: E96; SizeX_mm: 3.2; SizeY_mm: 1.6; SizeZ_mm: 1.35; Value2: 0.5W; SizeArea_mm2: 5.12; AEC Qualified: Y; AEC Grade: 0; AEC Category: Q200
R283 R294 R304 R321 = CMP-0025828-4: RES, 56 k, 5%, 0.1 W, AEC-Q200 Grade 0, 0603; Manufacturer: Vishay-Dale; Power_W: 100mW; TempCo: 200 ppm/C; Value_Code: 56k0; Value: 56k; EIA_Code: E24; SizeX_mm: 1.6; SizeY_mm: 0.8; SizeZ_mm: 1; Value2: 0.1W; SizeArea_mm2: 1.28; AEC Qualified: Y; VDC_V: 75V; AEC Category: Q200; AEC Grade: 0
R284 R287 R295 R298 R305 R308 R322 R325 = CMP-0021998-4: RES, 10.0 k, 1%, 0.1 W, AEC-Q200 Grade 0, 0603; Manufacturer: Vishay-Dale; Power_W: 100mW; TempCo: 100 ppm/C; Value_Code: 10k0; Value: 10.0k; EIA_Code: E96; Res_ohm: 10k; SizeX_mm: 1.6; SizeY_mm: 0.8; SizeZ_mm: 1; Value2: 0.1W; SizeArea_mm2: 1.28; AEC Qualified: Y; VDC_V: 75V; AEC Category: Q200; AEC Grade: 0
R285 R296 R306 R323 = CMP-0022746-5: RES, 10.0 k, 1%, 0.1 W, 0603; Manufacturer: Yageo; Power_W: 100mW; TempCo: 100 ppm/C; Value_Code: 10k0; Value: 10.0k; EIA_Code: E96; Res_ohm: 10k; SizeX_mm: 1.6; SizeY_mm: 0.8; SizeZ_mm: 1; Value2: 0.1W; SizeArea_mm2: 1.28; AEC Qualified: N; VDC_V: 75V; AEC Category: Q200; SizeAreaWB_mm2: 4.68
R286 R297 R307 R324 = CMP-0022961-4: RES, 270 k, 1%, 0.1 W, 0603; Manufacturer: Yageo; Power_W: 100mW; TempCo: 100 ppm/C; Value: 270k; SizeX_mm: 1.6; SizeY_mm: 0.8; SizeZ_mm: 1; Value2: 0.1W; SizeArea_mm2: 1.28; AEC Qualified: N; VDC_V: 75V; AEC Category: Q200; SizeAreaWB_mm2: 4.68
R288 R299 R309 R326 = CMP-0022735-5: RES, 100 k, 1%, 0.1 W, 0603; Manufacturer: Yageo; Power_W: 100mW; TempCo: 100 ppm/C; Value: 100k; EIA_Code: E96; SizeX_mm: 1.6; SizeY_mm: 0.8; SizeZ_mm: 1; Value2: 0.1W; SizeArea_mm2: 1.28; AEC Qualified: N; VDC_V: 75V; AEC Category: Q200; SizeAreaWB_mm2: 4.68
R289 R300 R310 R327 = CMP-0023289-4: RES, 825 k, 1%, 0.1 W, 0603; Manufacturer: Yageo; Power_W: 100mW; TempCo: 100 ppm/C; Value: 825k; EIA_Code: E96; SizeX_mm: 1.6; SizeY_mm: 0.8; SizeZ_mm: 1; Value2: 0.1W; SizeArea_mm2: 1.28; AEC Qualified: N; VDC_V: 75V; AEC Category: Q200; SizeAreaWB_mm2: 4.68
R290 R301 R311 R328 = CMP-0023259-5: RES, 71.5 k, 1%, 0.1 W, 0603; Manufacturer: Yageo; Power_W: 100mW; TempCo: 100 ppm/C; Value_Code: 71k5; Value: 71.5k; EIA_Code: E96; SizeX_mm: 1.6; SizeY_mm: 0.8; SizeZ_mm: 1; Value2: 0.1W; SizeArea_mm2: 1.28; AEC Qualified: N; VDC_V: 75V; AEC Category: Q200; SizeAreaWB_mm2: 4.68
R293 = CMP-0026696-1: RES, 33.0, 1%, 0.1 W, 0402; Manufacturer: Panasonic; Power_W: 100mW; TempCo: 100 ppm/C; Value_Code: 33R0; U/M: EA; Value: 33.0; Res_ohm: 33; SizeX_mm: 1; SizeY_mm: 0.5; SizeZ_mm: 0.6; Value2: 0.1W; VDC_V: 50V; AEC Category: Q200
R312-R314 = CMP-0124370-1: 680 kOhms ±0.1% 0.2W, 1/5W Chip Resistor 0805 (2012 Metric) Anti-Sulfur, Automotive AEC-Q200, High Voltage, Moisture Resistant Thin Film; Manufacturer: Vishay; AEC Grade: Grade 1; AEC Qualified: Yes; Power_W: 200mW; SizeZ_mm: 0.55mm; TempCo: 25ppm/°C; VDC_V: 450V
R315 = CMP-0122747-1: 8 kOhms ±0.1% 0.1W, 1/10W Chip Resistor 0603 (1608 Metric) Thin Film; Manufacturer: Yageo; AEC Qualified: No; Power_W: 100mW; SizeZ_mm: 0.55mm; TempCo: 50ppm/°C; VDC_V: 75V
U27 U31 U36 U42 = CMP-0123798-1: Manufacturer: Texas Instruments; SizeZ_mm: 2.35mm; Standoff Height: 0mm
U28 U32 U37 U43 = CMP-0085676-1: High Speed, Robust EMC Reinforced Dual-Channel Digital Isolator, DWV0008A (SOIC-8); Alternate Manufacturer: Texas Instruments; Alternate PartNumber: ISO7721FDWVR; Rating: Catalog; SizeX_mm: 11.5; SizeArea_mm2: 67.275; CompType: IC; AEC Qualified: N; SizeY_mm: 5.85; SizeAreaWB_mm2: 105.975; SizeZ_mm: 2.8; AEC Category: Q200
U29 U34 U39 U44 = CMP-0120108-2: 1.5W, High-Density, >5 kVRMS Isolated DC-DC Converter; Manufacturer: Texas Instruments; SizeZ_mm: 2.6mm; AEC Qualified: No; Max Supply Voltage: 5.5V; Min Supply Voltage: 4.5V; Number Of Outputs: 1; Output Type: AdjustableProgrammable; Output Voltage: 5/5.5V; Standoff Height: 0.14mm; AEC Category: Q200; CompType: IC
U30 U35 U40 U45 = CMP-0013231-2: 28-V Output Voltage Boost Converter with Power Diode and Isolation Switch, DBV0006A (SOT-6); Manufacturer: Texas Instruments; Alternate PartNumber: TLV61046ADBVT; SizeX_mm: 2.8; SizeY_mm: 2.9; CompType: IC; SizeZ_mm: 1.45; SizeArea_mm2: 8.12; SizeAreaWB_mm2: 14.82; U/M: EA
U33 = CMP-0051217-4: Single 3-Input Positive-AND Gate, DRY0006A (USON-6); Manufacturer: Texas Instruments; Output Type: CMOS; Bits(#): 1; Input Type: CMOS/TTL; Technology Family: LVC; Schmitt Trigger: No; VCC(Max)(V): 5.5; Gate Type: AND; Rating: Catalog; Output Drive (IOL/IOH)(Max)(mA): 32/-32; ICC @ Nom Voltage(Max)(mA): 0.01; VCC(Min)(V): 1.65; F @ Nom Voltage(Max)(Mhz): 150; Logic: True; Voltage(Nom)(V): 1.8,2.5,3.3,5; tpd @ Nom Voltage(Max)(ns): 20,7.8,6.2,4.6; AEC Category: Q200; AEC Qualified: N; CompType: IC; SizeAreaWB_mm2: 4.9; SizeArea_mm2: 1.45; SizeX_mm: 1.0; SizeZ_mm: 0.6
U38 = CMP-0070963-2: Micropower, 150mA Low-Dropout CMOS Voltage Regulator, 5-pin SC-70, Pb-Free; Manufacturer: Texas Instruments; CompType: LDO IC; PackageTopMarking: L5B*XTT; PowerWise: N; AEC Category: Q200; SizeAreaWB_mm2: 9.3; SizeArea_mm2: 4.2; SizeX_mm: 2.1; SizeY_mm: 2.0; SizeZ_mm: 1.1
U41 = CMP-0124047-1: Precision, 2V Input, Basic and Reinforced Isolated Amplifiers With Fixed-Gain Differential Output; Manufacturer: Texas Instruments; SizeZ_mm: 2.8mm; AEC Qualified: No; Bandwidth: 110kHz; Input Bias Current: 3.5nA; Input Offset Voltage: 0.2mV; Max Supply Voltage: 5.5V; Min Supply Voltage: 3V; Number Of Channels: 1; Output Current Per Channel: 11mA; Response Time: 50us; Standoff Height: 0.36mm; TaMax_C: +125°C; TaMin_C: -40°C; TJmax_C: +150°C; Voltage Gain: 1V/V

## Sheet TIDA-010957-DCAC-EMI-Filter.SchDoc
size 431 x 279 mm; Date: Not shown in title block; ApprovedBy: Not shown in title block; CheckedBy: Not shown in title block; Author: Not shown in title block; CompanyName: Not shown in title block; Engineer: Not shown in title block; Organization: Not shown in title block; Address1: Not shown in title block; Address2: Not shown in title block; Address3: Not shown in title block; Address4: Not shown in title block; DocumentNumber: 2; Revision: Use project parameter SCH_Rev; SheetNumber: 5; SheetTotal: 12; PageSetup: Record=PageOptions¦CenterHorizontal=True¦CenterVertical=True¦PrintScale=1.00¦XCorrection=1.00¦YCorrection=1.00¦PrintKind=0¦BorderSize=5000000¦LeftOffset=0¦BottomOffset=0¦Orientation=2¦PaperLength=1000¦PaperWidth=1000¦Scale=100¦PaperSource=15¦PrintQuality=600¦MediaType=1¦DitherType=10¦PaperKind=Letter¦PrintScaleMode=1

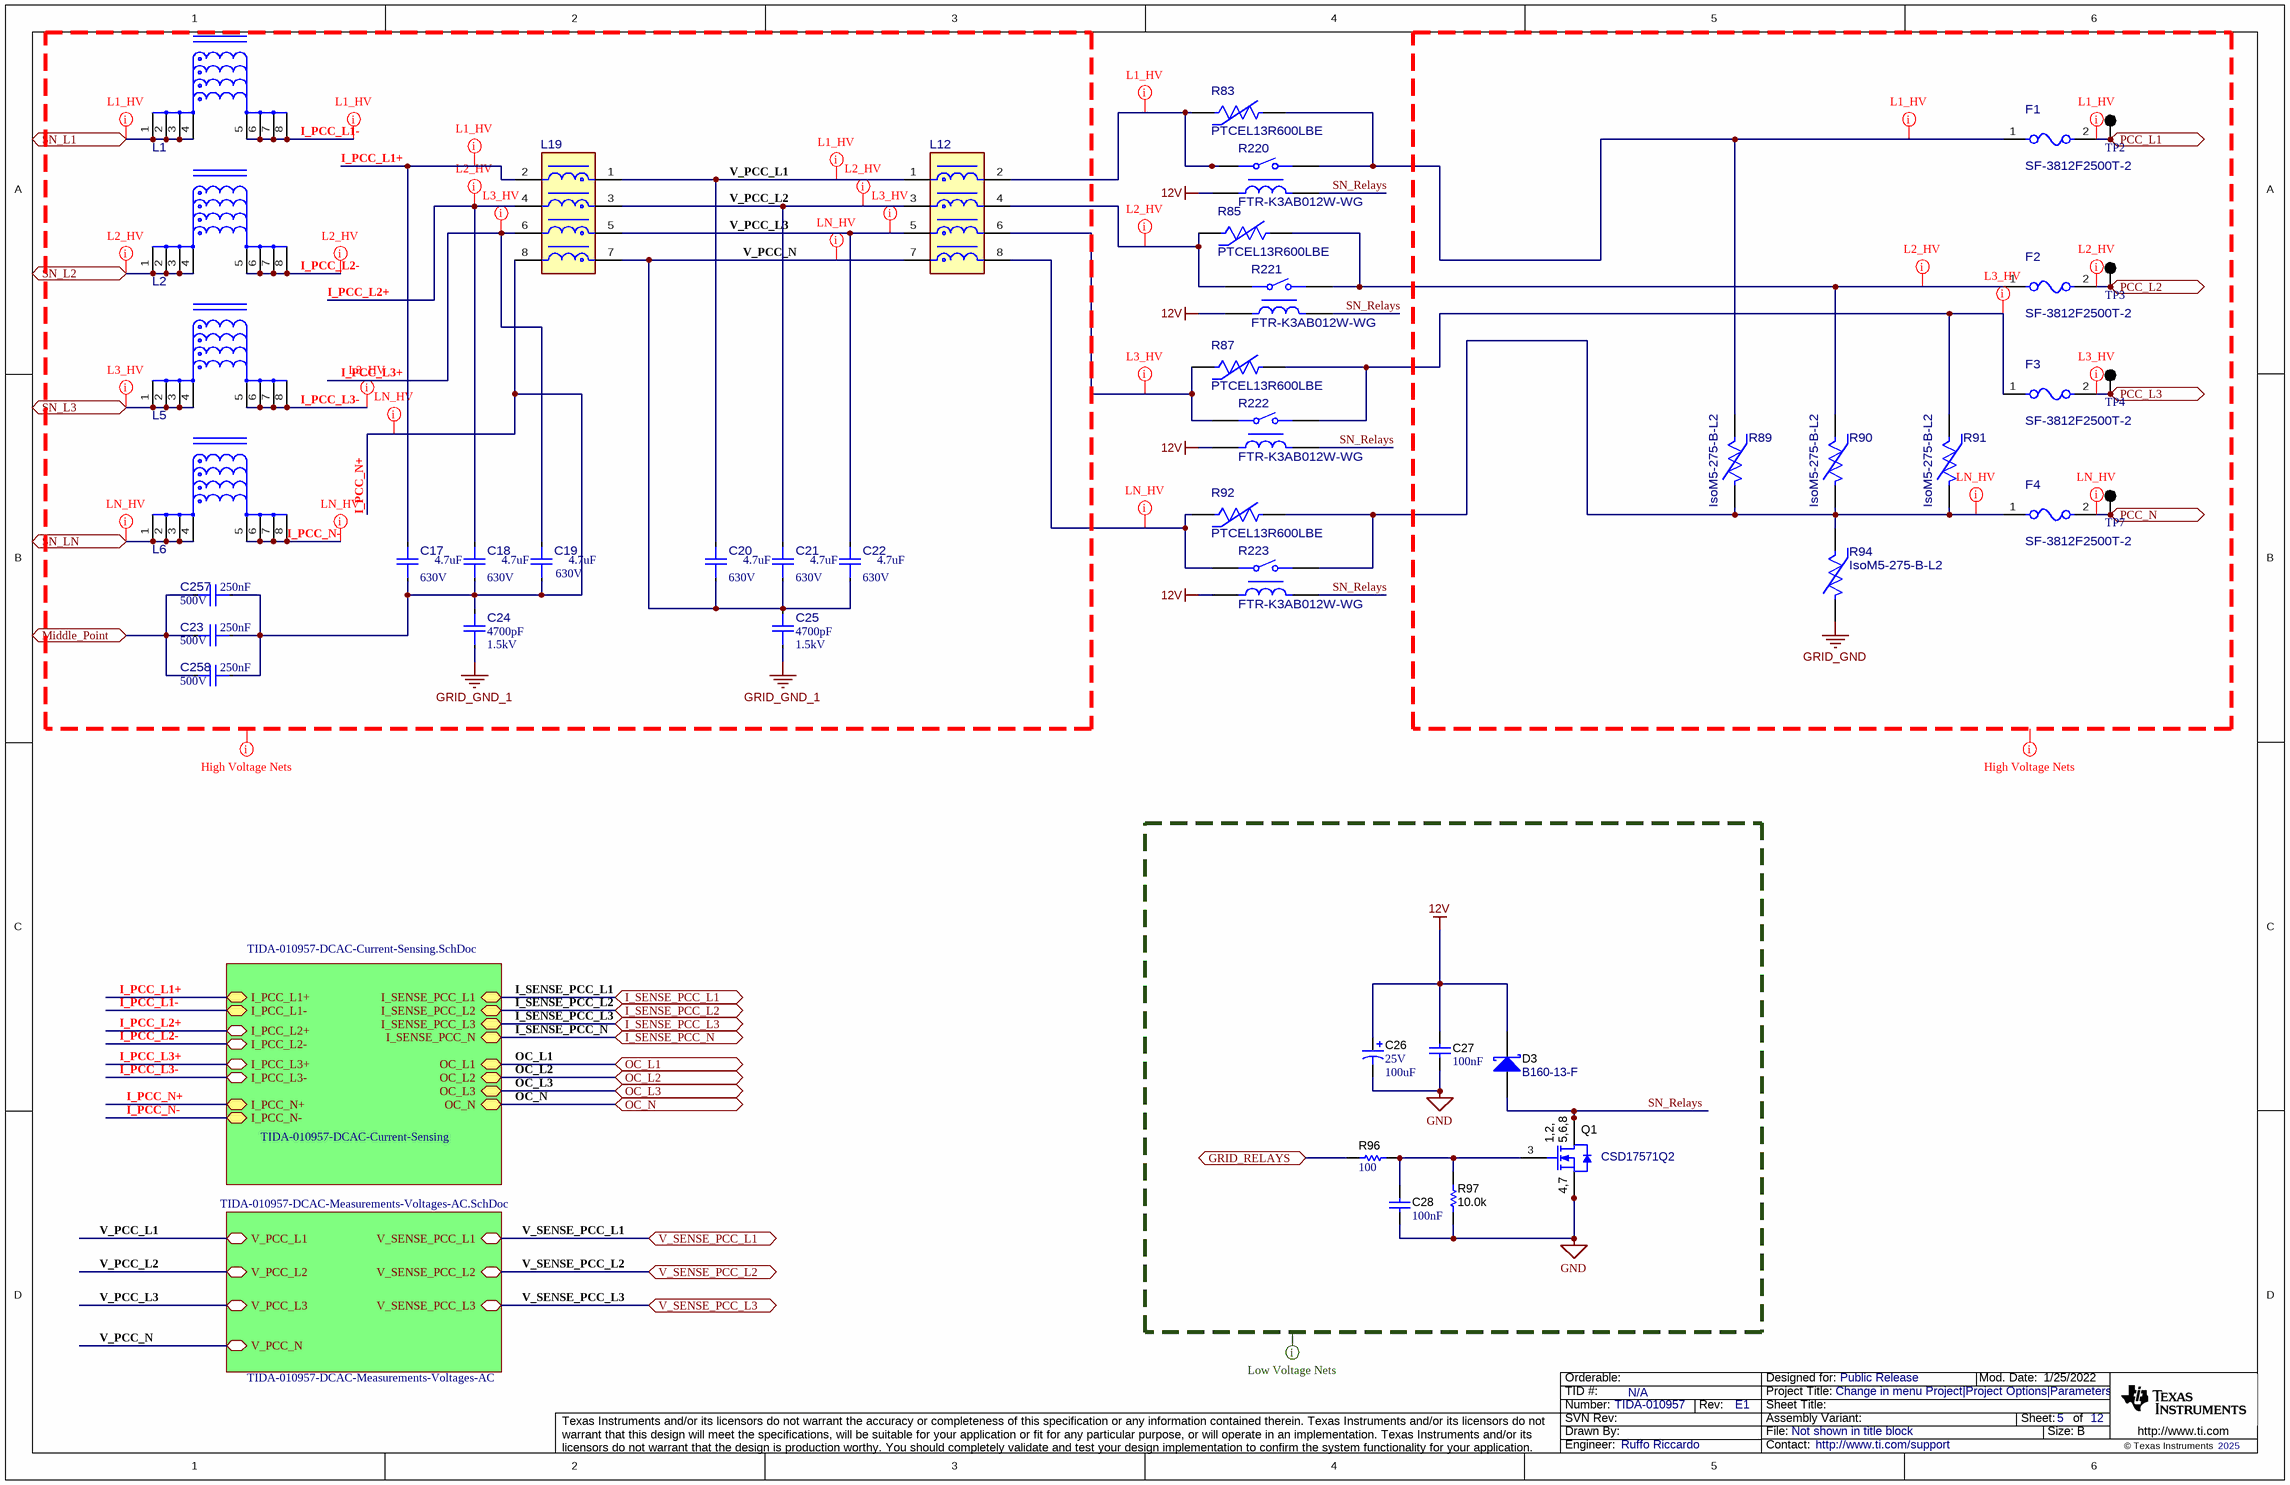
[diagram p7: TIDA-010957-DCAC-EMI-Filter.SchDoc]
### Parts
C17  ValueDisplayed: 4.7uF  VDC_V: 630V  [FP-R523R447050P1M_RADIAL-MFG]  (hidden comment: R523R447050P1M)
C18  ValueDisplayed: 4.7uF  VDC_V: 630V  [FP-R523R447050P1M_RADIAL-MFG]  (hidden comment: R523R447050P1M)
C19  ValueDisplayed: 4.7uF  VDC_V: 630V  [FP-R523R447050P1M_RADIAL-MFG]  (hidden comment: R523R447050P1M)
C20  ValueDisplayed: 4.7uF  VDC_V: 630V  [FP-R523R447050P1M_RADIAL-MFG]  (hidden comment: R523R447050P1M)
C21  ValueDisplayed: 4.7uF  VDC_V: 630V  [FP-R523R447050P1M_RADIAL-MFG]  (hidden comment: R523R447050P1M)
C22  ValueDisplayed: 4.7uF  VDC_V: 630V  [FP-R523R447050P1M_RADIAL-MFG]  (hidden comment: R523R447050P1M)
C23  ValueDisplayed: 250nF  VDC_V: 500V  [FP-B58043E5254M052_2220-MFG]  (hidden comment: B58043E5254M052)
C24  ValueDisplayed: 4700pF  VDC_V: 1.5kV  [FP-R413F147050T1K_RADIAL-MFG]  (hidden comment: R413F147050T1K)
C25  ValueDisplayed: 4700pF  VDC_V: 1.5kV  [FP-R413F147050T1K_RADIAL-MFG]  (hidden comment: R413F147050T1K)
C26  VDC_V: 25V  ValueDisplayed: 100uF  [FM_630x1120]  (hidden comment: EEU-FM1E101)
C27  Cap_F: 100nF  [0603]  (hidden comment: 06033C104JAT2A)
C28  Cap_F: 100nF  [0603]  (hidden comment: 06033C104JAT2A)
C257  ValueDisplayed: 250nF  VDC_V: 500V  [FP-B58043E5254M052_2220-MFG]  (hidden comment: B58043E5254M052)
C258  ValueDisplayed: 250nF  VDC_V: 500V  [FP-B58043E5254M052_2220-MFG]  (hidden comment: B58043E5254M052)
D3  B160-13-F  [SMA]
F1  SF-3812F2500T-2  [FP-SF-3812F2500T-2_SMD2-MFG]
F2  SF-3812F2500T-2  [FP-SF-3812F2500T-2_SMD2-MFG]
F3  SF-3812F2500T-2  [FP-SF-3812F2500T-2_SMD2-MFG]
F4  SF-3812F2500T-2  [FP-SF-3812F2500T-2_SMD2-MFG]
L1  B181179 V0 D6938  [FP-B181179 V0 D6938_PTH8-MFG]  (value not drawn)
L2  B181179 V0 D6938  [FP-B181179 V0 D6938_PTH8-MFG]  (value not drawn)
L5  B181179 V0 D6938  [FP-B181179 V0 D6938_PTH8-MFG]  (value not drawn)
L6  B181179 V0 D6938  [FP-B181179 V0 D6938_PTH8-MFG]  (value not drawn)
L12  B181178 V0 D6937  [FP-B181178 V0 D6937_PTH8-MFG]  (value not drawn)
L19  B181178 V0 D6937  [FP-B181178 V0 D6937_PTH8-MFG]  (value not drawn)
Q1  CSD17571Q2  [DQK0006C]
R83  PTCEL13R600LBE  [FP-PTCEL13R600LBE_RADIAL-MFG]
R85  PTCEL13R600LBE  [FP-PTCEL13R600LBE_RADIAL-MFG]
R87  PTCEL13R600LBE  [FP-PTCEL13R600LBE_RADIAL-MFG]
R89  IsoM5-275-B-L2  [FP-IsoM5-275-B-L2_RADIAL-MFG]
R90  IsoM5-275-B-L2  [FP-IsoM5-275-B-L2_RADIAL-MFG]
R91  IsoM5-275-B-L2  [FP-IsoM5-275-B-L2_RADIAL-MFG]
R92  PTCEL13R600LBE  [FP-PTCEL13R600LBE_RADIAL-MFG]
R94  IsoM5-275-B-L2  [FP-IsoM5-275-B-L2_RADIAL-MFG]
R96  ValueDisplayed: 100  [0402L]  (hidden comment: ERJ-2RKF1000X)
R97  ValueDisplayed: 10.0k  [0603]  (hidden comment: CRCW060310K0FKEA)
R220  FTR-K3AB012W-WG  [FP-FTR-K3AB012W-WG_PTH_RELAY_30MM1_15MM7-MFG]
R221  FTR-K3AB012W-WG  [FP-FTR-K3AB012W-WG_PTH_RELAY_30MM1_15MM7-MFG]
R222  FTR-K3AB012W-WG  [FP-FTR-K3AB012W-WG_PTH_RELAY_30MM1_15MM7-MFG]
R223  FTR-K3AB012W-WG  [FP-FTR-K3AB012W-WG_PTH_RELAY_30MM1_15MM7-MFG]
TP2  5011  [Keystone5011]  (value not drawn)
TP3  5011  [Keystone5011]  (value not drawn)
TP4  5011  [Keystone5011]  (value not drawn)
TP7  5011  [Keystone5011]  (value not drawn)

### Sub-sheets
TIDA-010957-DCAC-Current-Sensing = TIDA-010957-DCAC-Current-Sensing.SchDoc: I_SENSE_PCC_L1 (bidir), I_SENSE_PCC_L2 (bidir), I_SENSE_PCC_L3 (bidir), I_PCC_L1+ (bidir), I_PCC_L1- (bidir), I_PCC_L2+ (bidir), I_PCC_L2- (bidir), I_PCC_L3+ (bidir), I_PCC_L3- (bidir), OC_L1 (bidir), OC_L2 (bidir), OC_L3 (bidir), I_PCC_N+ (bidir), I_PCC_N- (bidir), OC_N (bidir), I_SENSE_PCC_N (bidir)
TIDA-010957-DCAC-Measurements-Voltages-AC = TIDA-010957-DCAC-Measurements-Voltages-AC.SchDoc: V_PCC_L1 (bidir), V_PCC_N (bidir), V_PCC_L2 (bidir), V_PCC_L3 (bidir), V_SENSE_PCC_L1 (bidir), V_SENSE_PCC_L2 (bidir), V_SENSE_PCC_L3 (bidir)

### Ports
GRID_RELAYS (bidir), I_SENSE_PCC_L1 (bidir), I_SENSE_PCC_L2 (bidir), I_SENSE_PCC_L3 (bidir), I_SENSE_PCC_N (bidir), Middle_Point (bidir), OC_L1 (bidir), OC_L2 (bidir), OC_L3 (bidir), OC_N (bidir), PCC_L1 (bidir), PCC_L2 (bidir), PCC_L3 (bidir), PCC_N (bidir), SN_L1 (bidir), SN_L2 (bidir), SN_L3 (bidir), SN_LN (bidir), V_SENSE_PCC_L1 (bidir), V_SENSE_PCC_L2 (bidir), V_SENSE_PCC_L3 (bidir)

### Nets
12V: C26.1(+) C27.1 D3.1(K) R220.1 R221.1 R222.1 R223.1
GND: C26.2(-) C27.2 C28.2 Q1.4(S) Q1.7(S) R97.1
GRID_GND: R94.1
GRID_GND_1: C24.1 C25.1
GRID_RELAYS: R96.1 ; port GRID_RELAYS
I_PCC_L1+: C17.2 L19.2 ; sheet TIDA-010957-DCAC-Current-Sensing/I_PCC_L1+
I_PCC_L1-: L1.5 L1.6 L1.7 L1.8 ; sheet TIDA-010957-DCAC-Current-Sensing/I_PCC_L1-
I_PCC_L2+: C18.2 L19.4 ; sheet TIDA-010957-DCAC-Current-Sensing/I_PCC_L2+
I_PCC_L2-: L2.5 L2.6 L2.7 L2.8 ; sheet TIDA-010957-DCAC-Current-Sensing/I_PCC_L2-
I_PCC_L3+: C19.2 L19.6 ; sheet TIDA-010957-DCAC-Current-Sensing/I_PCC_L3+
I_PCC_L3-: L5.5 L5.6 L5.7 L5.8 ; sheet TIDA-010957-DCAC-Current-Sensing/I_PCC_L3-
I_PCC_N+: C17.1 C18.1 C19.1 C23.1 C24.2 C257.1 C258.1 L19.8 ; sheet TIDA-010957-DCAC-Current-Sensing/I_PCC_N+
I_PCC_N-: L6.5 L6.6 L6.7 L6.8 ; sheet TIDA-010957-DCAC-Current-Sensing/I_PCC_N-
I_SENSE_PCC_L1: port I_SENSE_PCC_L1, sheet TIDA-010957-DCAC-Current-Sensing/I_SENSE_PCC_L1
I_SENSE_PCC_L2: port I_SENSE_PCC_L2, sheet TIDA-010957-DCAC-Current-Sensing/I_SENSE_PCC_L2
I_SENSE_PCC_L3: port I_SENSE_PCC_L3, sheet TIDA-010957-DCAC-Current-Sensing/I_SENSE_PCC_L3
I_SENSE_PCC_N: port I_SENSE_PCC_N, sheet TIDA-010957-DCAC-Current-Sensing/I_SENSE_PCC_N
Middle_Point: C23.2 C257.2 C258.2 ; port Middle_Point
OC_L1: port OC_L1, sheet TIDA-010957-DCAC-Current-Sensing/OC_L1
OC_L2: port OC_L2, sheet TIDA-010957-DCAC-Current-Sensing/OC_L2
OC_L3: port OC_L3, sheet TIDA-010957-DCAC-Current-Sensing/OC_L3
OC_N: port OC_N, sheet TIDA-010957-DCAC-Current-Sensing/OC_N
PCC_L1: F1.2 TP2.1 ; port PCC_L1
PCC_L2: F2.2 TP3.1 ; port PCC_L2
PCC_L3: F3.2 TP4.1 ; port PCC_L3
PCC_N: F4.2 TP7.1 ; port PCC_N
SN_L1: L1.1 L1.2 L1.3 L1.4 ; port SN_L1
SN_L2: L2.1 L2.2 L2.3 L2.4 ; port SN_L2
SN_L3: L5.1 L5.2 L5.3 L5.4 ; port SN_L3
SN_LN: L6.1 L6.2 L6.3 L6.4 ; port SN_LN
SN_Relays: D3.2(A) Q1.1(D) Q1.2(D) Q1.5(D) Q1.6(D) Q1.8(D) R220.2 R221.2 R222.2 R223.2
V_PCC_L1: C20.2 L12.1 L19.1 ; sheet TIDA-010957-DCAC-Measurements-Voltages-AC/V_PCC_L1
V_PCC_L2: C21.2 L12.3 L19.3 ; sheet TIDA-010957-DCAC-Measurements-Voltages-AC/V_PCC_L2
V_PCC_L3: C22.2 L12.5 L19.5 ; sheet TIDA-010957-DCAC-Measurements-Voltages-AC/V_PCC_L3
V_PCC_N: C20.1 C21.1 C22.1 C25.2 L12.7 L19.7 ; sheet TIDA-010957-DCAC-Measurements-Voltages-AC/V_PCC_N
V_SENSE_PCC_L1: port V_SENSE_PCC_L1, sheet TIDA-010957-DCAC-Measurements-Voltages-AC/V_SENSE_PCC_L1
V_SENSE_PCC_L2: port V_SENSE_PCC_L2, sheet TIDA-010957-DCAC-Measurements-Voltages-AC/V_SENSE_PCC_L2
V_SENSE_PCC_L3: port V_SENSE_PCC_L3, sheet TIDA-010957-DCAC-Measurements-Voltages-AC/V_SENSE_PCC_L3
NetC28_1: C28.1 Q1.3(G) R96.2 R97.2
NetF1_1: F1.1 R83.2 R89.2 R220.4
NetF2_1: F2.1 R85.2 R90.2 R221.4
NetF3_1: F3.1 R87.2 R91.2 R222.4
NetF4_1: F4.1 R89.1 R90.1 R91.1 R92.2 R94.2 R223.4
NetL12_2: L12.2 R83.1 R220.3
NetL12_4: L12.4 R85.1 R221.3
NetL12_6: L12.6 R87.1 R222.3
NetL12_8: L12.8 R92.1 R223.3

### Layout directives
net class LV_NET: 12V, GND, SN_Relays
net class HV_NET: GRID_GND, GRID_GND_1, I_PCC_L1+, I_PCC_L1-, I_PCC_L2+, I_PCC_L2-, I_PCC_L3+, I_PCC_L3-, I_PCC_N+, I_PCC_N-, V_PCC_L1, V_PCC_L2, V_PCC_L3, V_PCC_N
net class L2_HV: I_PCC_L2+, I_PCC_L2-, NetF2_1, NetL12_4, PCC_L2, SN_L2, V_PCC_L2
net class L1_HV: I_PCC_L1+, I_PCC_L1-, NetF1_1, NetL12_2, PCC_L1, SN_L1, V_PCC_L1
net class L3_HV: I_PCC_L3+, I_PCC_L3-, NetF3_1, NetL12_6, PCC_L3, SN_L3, V_PCC_L3
net class LN_HV: I_PCC_N+, I_PCC_N-, NetF4_1, NetL12_8, PCC_N, SN_LN, V_PCC_N

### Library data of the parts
C17-C22 = CMP-0098409-1: 4.7 µF Film Capacitor 310V 630V Polypropylene (PP), Metallized Radial; Manufacturer: KEMET; AEC Grade: Grade 2; AEC Qualified: Yes; Cap_F: 4.7µF; SizeZ_mm: 28.1mm; Tolerance_%: 20%; VAC_X: X2; Value: 4.7µF
C23 C257 C258 = CMP-0098327-1: 0.25 µF ±20% 500V Ceramic Capacitor 2220 (5750 Metric); Manufacturer: TDK; AEC Qualified: No; SizeZ_mm: 1.6mm; Value: 250nF
C24 C25 = CMP-0098408-1: Cap Film 0.0047uF 1500V PP 10% Dipped 10mm 125°C Bulk; Manufacturer: KEMET; AEC Grade: Grade 1; AEC Qualified: Yes; Cap_F: 4.7nF; SizeZ_mm: 11.1mm; VAC: 300V; VAC_Y: Y2; Value: 4.7nF
C26 = CMP-0010339-1: CAP, AL, 100 uF, 25 V, +/- 20%, 0.13 ohm, TH; Manufacturer: Panasonic; TaMin_C: -40°C; ESR_ohm: 0.13; Polarized: Y; SizeAreaWB_mm2: 68.89; U/M: EA; Value: 100uF; TaMax_C: 105°C; SizeZ_mm: 12.7; SizeX_mm: 6.3; Cap_Case: 6.3x11.2; SizeArea_mm2: 39.69; CompType: Capacitor; AEC Qualified: N; Cap_F: 100µF; IRMS_A: 455mA; AEC Category: Q200
C27 C28 = CMP-0006752-5: as C186 on sheet TIDA-010957-DCAC-Switching-Stage-GaN-TOLT
D3 = CMP-0028389-2: Diode, Schottky, 60 V, 1 A, SMA; Manufacturer: Diodes Inc.; Green_Lifecycle: Not Set; SizeAreaWB_mm2: 37.3428; Green_REACh: Incomplete; TJmax_C: 150°C; AEC Category: Q101; SizeZ_mm: 2.87; RJC_CperW: 20; Io_A: 1A; SizeArea_mm2: 16.3228; Vf_V: 700mV; Value2: 0.7V; SizeY_mm: 2.92; Vr_V: 60V; SizeX_mm: 5.59; Value: 60V
F1-F4 = CMP-0122960-1: 25 A 250 V AC 80 V DC Fuse Board Mount (Cartridge Style Excluded) Surface Mount 2-SMD, Square End Block; Manufacturer: Bourns; Interrupt_AC: 100A; Interrupt_DC: 130A; MeltingTyp: 625A2Sec; SizeZ_mm: 3.3mm; VAC_V: 250V; Fuse Speed: Fast; AEC Qualified: No; Fuse Current: 25A; Res_ohm: 0.0024Ω
L1 L2 L5 L6 = CMP-0124380-1: Boost Inductor TIDA-010957; Manufacturer: Bourns; AEC Qualified: No; DCR_ohm: 11.11m; Ind_H: 87µH; Isat: 42A; SizeZ_mm: 49.4mm; Value: 87uH; Test Frequency: 100kHz; Tolerance_%: 10%
L12 L19 = CMP-0124379-2: 4-Phase CMC; Manufacturer: Bourns; Ind_H: 3mH; SizeZ_mm: 30.3mm; AEC Qualified: No; Imax_A: 25A; Test Frequency: 100kHz; Tolerance_%: +50/-35%
Q1 = CMP-0000585-1: MOSFET, N-CH, 30 V, 22 A, DQK0006C (WSON-6); Alternate Manufacturer: None; Manufacturer: Texas Instruments; SizeZ_mm: 0.8; ChType: N; Value2: 2.4 nC; Value1: 0.02; VdsMax_V: 30V; SizeX_mm: 2; Vgs_V: 20V; Value: 30V; Rdson45_ohm: 0.029; SizeArea_mm2: 4; AEC Category: Q101; IdsMax_A: 22A; SizeAreaWB_mm2: 9; U/M: EA; QgTyp_nC: 2.4
R83 R85 R87 R92 = CMP-0097004-1: PTCEL Series 500 V 60 Ohm ±30 % Radial Inrush Current Limiter PTC Thermistor; Manufacturer: Vishay Bccomponents; Value: 60Ω; SizeZ_mm: 17mm; AEC Qualified: Yes; Hold Current: 120mA; Tolerance_%: 30%; VDC_V: 500V; AEC Grade: Grade 2
R89-R91 R94 = CMP-0096768-1: 5 kA Varistor 1 Circuit Through Hole Disc 17mm; Manufacturer: Bourns; AEC Qualified: No; SizeZ_mm: 23mm; VDC_V: 350V; Vc: 100A; ValueDisplayed: 40pF; Clamping Voltage: 730V
R96 = CMP-0026656-1: RES, 100, 1%, 0.1 W, 0402; Manufacturer: Panasonic; Power_W: 100mW; TempCo: 100 ppm/C; Value_Code: 100R; U/M: EA; Value: 100; EIA_Code: E96; SizeX_mm: 1; SizeY_mm: 0.5; SizeZ_mm: 0.6; Value2: 0.1W; VDC_V: 50V; AEC Category: Q200
R97 = CMP-0021998-4: as R284 on sheet TIDA-010957-DCAC-Switching-Stage-GaN-TOLT
R220-R223 = CMP-0124381-1: Power Relay 12VDC 25A SPST-NO(30.1x15.7x23.3)mm THT; Manufacturer: FCL Components; Coil Power_W: 780mW; Coil Type: Non-Latching; Coil Voltage_VDC: 12V; SizeZ_mm: 23.6mm; AEC Qualified: No; Coil Resistance: 185Ω
TP2-TP4 TP7 = CMP-0055148-2: Test Point, Multipurpose, Black, TH; Manufacturer: Keystone Electronics; CNHeader: FALSE; ContactFinish: Silver; Green_REACh: Passed; Green_Lifecycle: Active; CT: TRUE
